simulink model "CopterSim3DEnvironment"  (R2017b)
settings: Solver=ode4  StartTime=0.0  StopTime=2000  FixedStep=0.001  RelTol=1e-3
PreLoadFcn:
  | filepath  = fileparts(get_param(bdroot, 'FileName'));
  | cd(filepath);
InitFcn:
  | if exist('Init_control.m','file')
  |      Init_control;
  | end
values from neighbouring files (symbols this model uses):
  Kd_RP_AgngleRate = 0.005    [Init_control.m]    (also in Init.m = 0.001)
  Kd_YAW_AngleRate = 0.05    [Init_control.m]    (also in Init.m = 0)
  Ki_RP_AgngleRate = 0.01    [Init_control.m]    (also in Init.m = 0.02)
  Ki_YAW_AngleRate = 0.8    [Init_control.m]    (also in Init.m = 0.1)
  KiPitchAttitude = 0.0552303199591522 / kFactor    (= 0.0460252666326)    [Init_control.m]
  KiRollAttitude = 0.0552303199591522 / kFactor    (= 0.0460252666326)    [Init_control.m]
  Kp_RP_AgngleRate = 0.55    [Init_control.m]    (also in Init.m = 0.1)
  Kp_RP_ANGLE = 6.5    [Init_control.m]    (also in Init.m)
  Kp_YAW_AngleRate = 3.2    [Init_control.m]    (also in Init.m = 0.3)
  MAX_CONTROL_ANGLE_RATE_Y = 90    [Init_control.m]    (also in Init.m = 200)
  MAX_CONTROL_ANGLE_RP = 45    [Init_control.m]
  ModelInit_RPM = 0    [Init.m]
  ModelParam_envAltitude = -50    [Init.m]
  ModelParam_GlobalNoiseGainSwitch = 0.4    [Init.m]
  ModelParam_GPSEphFinal = 0.3    [Init.m]
  ModelParam_GPSEpvFinal = 0.4    [Init.m]
  ModelParam_GPSFix3DFix = 3    [Init.m]
  ModelParam_GPSSatsVisible = 10    [Init.m]
  ModelParam_motorCr = 842.1    [Init.m]
  ModelParam_motorJm = 0.0001287    [Init.m]
  ModelParam_motorMinThr = 0.05    [Init.m]
  ModelParam_motorT = 0.0214    [Init.m]
  ModelParam_motorWb = 22.83    [Init.m]
  ModelParam_noiseBaroCoupleWithSpeed = 0    [Init.m]
  ModelParam_noiseGPSSampTime = 0.2    [Init.m]
  ModelParam_noisePowerIMU = 0    [Init.m]
  ModelParam_noisePowerOffGainAccel = 0.04    [Init.m]
  ModelParam_noisePowerOffGainAccelZ = 0.03    [Init.m]
  ModelParam_noisePowerOffGainGyro = 0.02    [Init.m]
  ModelParam_noisePowerOffGainGyroZ = 0.025    [Init.m]
  ModelParam_noisePowerOffGainMag = 0.02    [Init.m]
  ModelParam_noisePowerOffGainMagZ = 0.035    [Init.m]
  ModelParam_noisePowerOnGainAccel = 0.8    [Init.m]
  ModelParam_noisePowerOnGainAccelZ = 4.5    [Init.m]
  ModelParam_noisePowerOnGainGyro = 2    [Init.m]
  ModelParam_noisePowerOnGainGyroZ = 1    [Init.m]
  ModelParam_noisePowerOnGainMag = 0.025    [Init.m]
  ModelParam_noisePowerOnGainMagZ = 0.05    [Init.m]
  ModelParam_noiseSampleTimeAccel = 0.001    [Init.m]
  ModelParam_noiseSampleTimeGyro = 0.001    [Init.m]
  ModelParam_noiseSampleTimeMag = 0.01    [Init.m]
  ModelParam_noiseUpperGPS = 0.5    [Init.m]
  ModelParam_noiseUpperWindBodyRatio = 0    [Init.m]
  ModelParam_noiseWindSampTime = 0.001    [Init.m]
  ModelParam_rotorCm = 2.783e-07    [Init.m]
  ModelParam_rotorCt = 1.681e-05    [Init.m]
  ModelParam_timeSampBaro = 0.01    [Init.m]
  ModelParam_uavCCm = [0.0035 0.0039 0.0034]    [Init.m]
  ModelParam_uavCd = 0.055    [Init.m]
  ModelParam_uavDearo = 0.12    [Init.m]
  ModelParam_uavMass = 1.515    [Init.m]
  ModelParam_uavR = 0.225    [Init.m]
  ModelParam_uavType = int8(3)    [Init.m]
undefined symbols (not defined in the file or in its folder): a029, a452, b2ca, be23, CopterSim3DEnvironment, d291, d_i, da57f061, e227219c210b, Earth, earthRadius, f0d8, f8138af1, ff54be59cd06, h_i, ModelParam_GPSEpvInitial, ModelParam_GPSEpvTimeConstant, ModelParam_noiseLowPassFilterCoeAccel, ModelParam_noiseLowPassFilterCoeGyro, ModelParam_timeSamp, Newton, Raphson, Receive, Send, slider, WGS84
libraries: simulink x17, aerolibfltsims x4, aerolibtransform2 x3, sharedtransform x3, aerolibasang x3, aerolibatmos2 x2, sharedutil x2, aerolibutil x2, etargetslib x2, shared6dof x1, aerolibconvert2 x1, aerolibobsolete x1
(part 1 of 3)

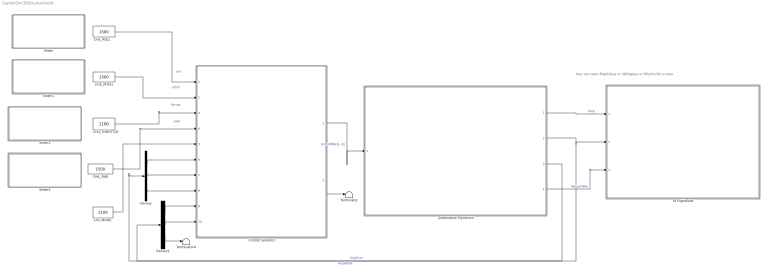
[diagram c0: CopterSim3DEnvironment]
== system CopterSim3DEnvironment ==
  note: Your can open FlightGear or 3DDisplay or RflySim3D to view
  note: roll
  note: pitch
  note: thrust
  note: yaw
  "     CH3_THROTTLR " : Constant  Value=1100  OutDataTypeStr=uint16
  "     CH4_YAW     " : Constant  Value=1500  OutDataTypeStr=uint16
  " CH2_PITCH " : Constant  Value=1500  OutDataTypeStr=uint16
  "CH1_ROLL   " : Constant  Value=1500  OutDataTypeStr=uint16
  "Ch5_MODE " : Constant  Value=1100  OutDataTypeStr=uint16
  Control System1 : Subsystem
  Demux : Demux  Outputs=3
  Demux1 : Demux  Outputs=3
  Quadcopter Dynamics : Subsystem
  Slider : Subsystem  DialogController=hmiCreateDDGDialog  IsWebBlock=on  mask(MWDashboardBlock){webBlockId=da57f061-4e57-426f-be23-e227219c210b, webBlockType=slider, ShowInLibBrowser=on, ShowInitialText=on, HMISrcModelName=CopterSim3DEnvironment}
      mask prompts: webBlockId "WebBlock Id"; webBlockType "WebBlock Type"; HMISrcModelName "Source Model"
      mask help: SimulinkHMI:dialogs:SliderDialogDesc
  Slider1 : Subsystem  DialogController=hmiCreateDDGDialog  IsWebBlock=on  mask(MWDashboardBlock){webBlockId=f8138af1-f0d8-4bb2-b2ca-4a41ecd2e2bf, webBlockType=slider, ShowInLibBrowser=on, ShowInitialText=on, HMISrcModelName=CopterSim3DEnvironment}
      mask prompts: webBlockId "WebBlock Id"; webBlockType "WebBlock Type"; HMISrcModelName "Source Model"
      mask help: SimulinkHMI:dialogs:SliderDialogDesc
  Slider2 : Subsystem  DialogController=hmiCreateDDGDialog  IsWebBlock=on  mask(MWDashboardBlock){webBlockId=6ace0251-812b-4be1-a029-ff54be59cd06, webBlockType=slider, ShowInLibBrowser=on, ShowInitialText=on, HMISrcModelName=CopterSim3DEnvironment}
      mask prompts: webBlockId "WebBlock Id"; webBlockType "WebBlock Type"; HMISrcModelName "Source Model"
      mask help: SimulinkHMI:dialogs:SliderDialogDesc
  Slider3 : Subsystem  DialogController=hmiCreateDDGDialog  IsWebBlock=on  mask(MWDashboardBlock){webBlockId=7791c665-d291-46cf-a452-489177f2fb62, webBlockType=slider, ShowInLibBrowser=on, ShowInitialText=on, HMISrcModelName=CopterSim3DEnvironment}
      mask prompts: webBlockId "WebBlock Id"; webBlockType "WebBlock Type"; HMISrcModelName "Source Model"
      mask help: SimulinkHMI:dialogs:SliderDialogDesc
  Terminator : Terminator
  Terminator4 : Terminator
  To FlightGear : Subsystem
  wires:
  Quadcopter Dynamics/1(PosE) -> To FlightGear/1(PosE)  "PosE"
  Control System1/2(LED) -> Terminator/1
  Quadcopter Dynamics/2(AngEuler) -> To FlightGear/2(AngEular), Demux1/1  "AngEular"
  "CH1_ROLL   "/1 -> Control System1/1(ch1)
  "     CH4_YAW     "/1 -> Control System1/4(ch4)
  "     CH3_THROTTLR "/1 -> Control System1/3(ch3)
  Quadcopter Dynamics/3(AngRateB) -> Demux/1  "AngRateB"
  "Ch5_MODE "/1 -> Control System1/5(ch5)
  Demux/1 -> Control System1/6(p)
  Demux/2 -> Control System1/7(q)
  Demux/3 -> Control System1/8(r)
  Demux1/1 -> Control System1/9(phi)
  Demux1/2 -> Control System1/10(theta)
  Demux1/3 -> Terminator4/1
  " CH2_PITCH "/1 -> Control System1/2(ch2)
  Control System1/1(PWM) -> Quadcopter Dynamics/1(inPWMs)  "8-D PWMs（0~1）"
  Quadcopter Dynamics/4(MotorRPMS) -> To FlightGear/3(MotorPWMs)  "MotorPWMs"

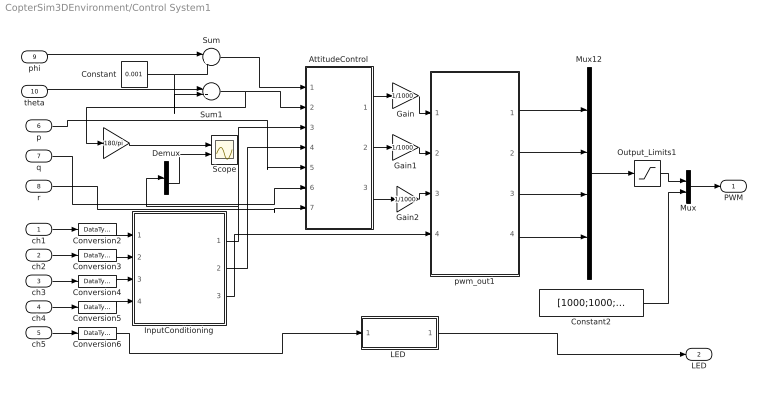
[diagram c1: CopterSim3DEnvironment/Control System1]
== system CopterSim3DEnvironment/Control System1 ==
  ch1 : Inport  OutDataTypeStr=uint16  PortDimensions=1
  ch2 : Inport  Port=2  OutDataTypeStr=uint16  PortDimensions=1
  ch3 : Inport  Port=3  OutDataTypeStr=uint16  PortDimensions=1
  ch4 : Inport  Port=4  OutDataTypeStr=uint16  PortDimensions=1
  ch5 : Inport  Port=5  OutDataTypeStr=uint16  PortDimensions=1  Interpolate=off
  p : Inport  Port=6  PortDimensions=1
  q : Inport  Port=7  PortDimensions=1
  r : Inport  Port=8  PortDimensions=1
  phi : Inport  Port=9  PortDimensions=1
  theta : Inport  Port=10  PortDimensions=1
  " " : Gain  Gain=180/pi
  AttitudeControl : Subsystem
  Constant : Constant  Value=0.001
  Constant2 : Constant  Value=[1000;1000;1000;1000]
  Conversion{2..6} (5 alike) : DataTypeConversion  OutDataTypeStr=double
  Demux : Demux  Outputs=2
  Gain : Gain  Gain=1/1000
  Gain1 : Gain  Gain=1/1000
  Gain2 : Gain  Gain=1/1000
  InputConditioning : Subsystem
  "LED " : Subsystem
  Mux : Mux  Inputs=2
  Mux12 : Mux
  Output_Limits1 : Saturate  UpperLimit=2000  LowerLimit=1000
  Scope : Scope  NumInputPorts=2
  Sum : Sum  Inputs=|++
  Sum1 : Sum  Inputs=|++
  pwm_out1 : MATLAB Function  TreatAsAtomicUnit=on  SystemSampleTime=0.004
  PWM : Outport  PortDimensions=8
  LED : Outport  Port=2  PortDimensions=1
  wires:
  InputConditioning/3(Thrust) -> pwm_out1/4(Thrust)
  Mux12/1 -> Output_Limits1/1
  Gain1/1 -> pwm_out1/2(Pitch)
  Gain/1 -> pwm_out1/1(Roll)
  ch3/1 -> Conversion4/1
  pwm_out1/1(M1) -> Mux12/1
  ch5/1 -> Conversion6/1
  pwm_out1/3(M3) -> Mux12/3
  pwm_out1/2(M2) -> Mux12/2
  r/1 -> AttitudeControl/7(r)
  AttitudeControl/1(Roll) -> Gain/1
  Gain2/1 -> pwm_out1/3(Yaw)
  InputConditioning/1(Roll_Pitch) -> Demux/1, AttitudeControl/3(roll_pitch)
  q/1 -> AttitudeControl/6(q)
  theta/1 -> Sum1/1
  InputConditioning/2(Yaw) -> AttitudeControl/4(yaw)
  p/1 -> AttitudeControl/5(p)
  ch4/1 -> Conversion5/1
  pwm_out1/4(M4) -> Mux12/4
  AttitudeControl/3(Yaw) -> Gain2/1
  AttitudeControl/2(Pitch) -> Gain1/1
  ch1/1 -> Conversion2/1
  "LED "/1(Out1) -> LED/1
  ch2/1 -> Conversion3/1
  Conversion6/1 -> "LED "/1(In1)
  Conversion2/1 -> InputConditioning/1(roll)
  Conversion5/1 -> InputConditioning/4(yaw)
  Conversion4/1 -> InputConditioning/3(thrust)
  Conversion3/1 -> InputConditioning/2(pitch)
  " "/1 -> Scope/1
  Demux/2 -> Scope/2
  phi/1 -> Sum/1
  Sum/1 -> AttitudeControl/1(phi)
  Sum1/1 -> " "/1, AttitudeControl/2(theta)
  Constant/1 -> Sum1/2, Sum/2
  Constant2/1 -> Mux/2
  Output_Limits1/1 -> Mux/1
  Mux/1 -> PWM/1

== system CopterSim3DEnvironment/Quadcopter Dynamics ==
  note: 电机转速
  note: 机体角速度
  note: 欧拉角
  note: 地面坐标系下位置
  note: 地面坐标系下速度
  note: 输入为8路1000~2000范围的信号
  note: Note2: There are three parameters essential for DLL model generation. They are "ModelInit_Inputs" (8D vector for input pwm signal initialization) in the "Motor Model" module, "ModelInit_PosE" (3D vector for position initialization) and "ModelInit_AngEuler" (3D vector for attitude initialization) in the "6DOF" module
  inPWMs : Inport  PortDimensions=8
  6DOF : Subsystem
  Bus Selector : BusSelector  OutputSignals=PosE,AngEuler,MotorRPMS,RateB
  Constant1 : Constant  Value=0
  Constant4 : Constant  Value=[1000;1000;1000;1000;1000;1000;1000;1000]
  Data Type Conversion{,1..3} (4 alike) : DataTypeConversion  OutDataTypeStr=double
  Environment Model : Subsystem
  Force and Moment Model : Subsystem
  Gain1 : Gain  Gain=1/1000
  Motor Model : Subsystem
  OutputSignals : Subsystem
  Rate Transition : RateTransition  OutPortSampleTime=ModelParam_BusSampleRate
  Rate Transition1 : RateTransition  OutPortSampleTime=ModelParam_BusSampleRate
  Selector : Selector  InputPortWidth=8  IndexOptions=Index vector (dialog)  Indices=[1 2 3 4]  OutputSizes=1
  SensorModel : Subsystem
  Sum3 : Sum  Inputs=|+-
  Terminator : Terminator
  Terminator1 : Terminator
  PosE : Outport
  AngEuler : Outport  Port=2
  AngRateB : Outport  Port=3
  MotorRPMS : Outport  Port=4
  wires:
  Selector/1 -> MotorRPMS/1
  Constant4/1 -> Sum3/2
  inPWMs/1 -> Sum3/1
  Constant1/1 -> Rate Transition1/1
  Sum3/1 -> Gain1/1
  Gain1/1 -> Rate Transition/1
  OutputSignals/17(PWMs) -> SensorModel/17(PWM)
  OutputSignals/13(<Rho>) -> SensorModel/13(<Rho>)
  OutputSignals/6(<wb>) -> SensorModel/6(<wb>)
  SensorModel/3(Vehile3DInfo) -> Bus Selector/1
  OutputSignals/12(<AirPressure>) -> SensorModel/12(<AirPressure>)
  OutputSignals/3(<Xe>) -> SensorModel/3(<Xe>)
  OutputSignals/5(<DCM>) -> SensorModel/5(<DCM>)
  OutputSignals/7(<dwb/dt>) -> SensorModel/7(<dwb/dt>)
  OutputSignals/9(<PosGPS>) -> SensorModel/9(<PosGPS>)
  OutputSignals/4(<Eular(rad)>) -> SensorModel/4(<Eular(rad)>)
  OutputSignals/10(<gravity>) -> SensorModel/10(<gravity>)
  OutputSignals/2(<Ve>) -> SensorModel/2(<Ve>)
  OutputSignals/16(<Fb>) -> SensorModel/16(<Fb>)
  OutputSignals/8(<AccB>) -> SensorModel/8(<AccB>)
  OutputSignals/15(<MotorRads>) -> SensorModel/15(MotorRads)
  Force and Moment Model/1(Force and Moment Model Bus) -> OutputSignals/4(Force and Moment Model Bus), 6DOF/1(Force and Moment Model Bus)  "Kinetics Info"
  Rate Transition/1 -> OutputSignals/6(PWM), Motor Model/1(pwm)
  SensorModel/1(MavLinkSensorData) -> Terminator/1
  6DOF/1(6DOF Bus) -> OutputSignals/5(6DOF Bus), Environment Model/1(6DOF Bus), Force and Moment Model/3(6DOF Bus)  "Kinematics Info"
  Rate Transition1/1 -> Force and Moment Model/4("tZ "), OutputSignals/3(zt)
  Motor Model/1(MotorRads) -> OutputSignals/2(MotorRads), Force and Moment Model/1(MotorRads)
  OutputSignals/1(TerrainZ) -> SensorModel/1(TerrainZ)
  OutputSignals/11(<TempC>) -> SensorModel/11(<TempC>)
  Environment Model/1(Environment Model Bus) -> OutputSignals/1(Environment Model Bus), Force and Moment Model/2(Environment Model Bus)  "Environment Info"
  OutputSignals/14(<Windb>) -> SensorModel/14(<Windb>)
  SensorModel/2(MavLinkGPSData) -> Terminator1/1
  Bus Selector/1 -> Data Type Conversion/1  "<PosE>"
  Bus Selector/2 -> Data Type Conversion1/1  "<AngEuler>"
  Bus Selector/4 -> Data Type Conversion3/1  "<RateB>"
  Bus Selector/3 -> Data Type Conversion2/1  "<MotorRPMS>"
  Data Type Conversion/1 -> PosE/1
  Data Type Conversion1/1 -> AngEuler/1
  Data Type Conversion2/1 -> Selector/1
  Data Type Conversion3/1 -> AngRateB/1

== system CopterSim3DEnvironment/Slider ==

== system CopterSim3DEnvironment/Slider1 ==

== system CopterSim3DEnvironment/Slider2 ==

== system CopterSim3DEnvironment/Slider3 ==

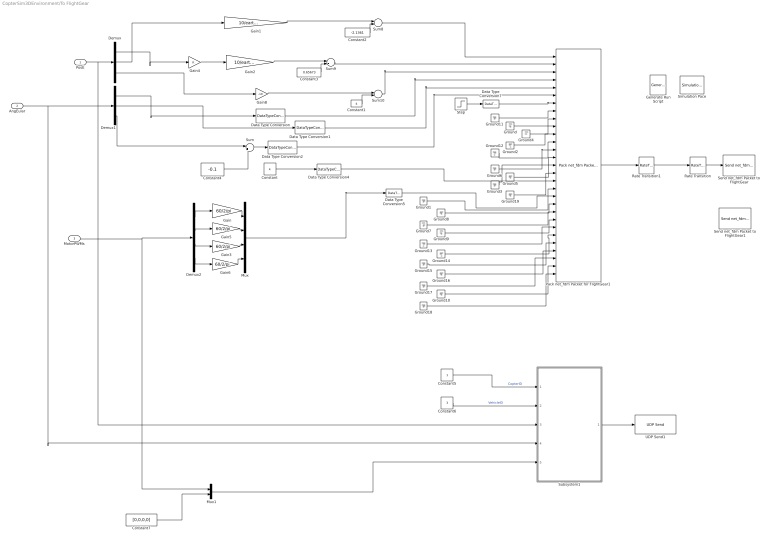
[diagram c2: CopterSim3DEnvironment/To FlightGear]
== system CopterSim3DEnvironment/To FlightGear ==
  PosE : Inport
  AngEular : Inport  Port=2
  MotorPWMs : Inport  Port=3
  Constant : Constant  Value=4
  Constant1 : Constant  Value=5  VectorParams1D=off
  Constant2 : Constant  Value=-2.1361  VectorParams1D=off
  Constant3 : Constant  Value=0.65673  VectorParams1D=off
  Constant4 : Constant  Value=-0.1  VectorParams1D=off
  Constant5 : Constant
  Constant6 : Constant  Value=3
  Constant7 : Constant  Value=[0,0,0,0]
  Data Type Conversion{,1..2,5,7} (5 alike) : DataTypeConversion  OutDataTypeStr=single
  Data Type Conversion4 : DataTypeConversion  OutDataTypeStr=uint32
  Demux : Demux  Outputs=3
  Demux1 : Demux  Outputs=3
  Demux2 : Demux
  Gain{,3,5..6} (4 alike) : Gain  Gain=60/2/pi
  Gain1 : Gain  Gain=10/earthRadius
  Gain2 : Gain  Gain=10/earthRadius
  Gain4 : Gain
  Gain8 : Gain  Gain=-10
  Generate Run Script : aerolibfltsims/Generate Run Script  OutputFileName=runfg.bat  FlightGearBaseDirectory=C:\Program Files\FlightGear 2016.1.2  GeometryModelName=Rotor4  DestinationPort=5502  OriginAddress=127.0.0.1  OriginPort=5505  LocalAddress=127.0.0.1  AirportId=KSF0  RunwayId=10L  InitialAltitude=0  InitialHeading=0  OffsetDistance=0  OffsetAzimuth=0  GenerateFile=off  Architecture=Default  dataFlow=Send-Receive
  Ground{,1..19} (20 alike) : Ground
  Mux : Mux
  Mux1 : Mux  Inputs=2
  Pack net_fdm Packet for FlightGear1 : aerolibfltsims/Pack net_fdm Packet for FlightGear  FlightGearVersion=v2016.1  ShowPositionAttitudeInputs=on  ShowVelocityAccelerationInputs=off  ShowControlSurfacePositionInputs=on  ShowEngineFuelInputs=on  ShowLandingGearInputs=off  ShowEnvironmentInputs=off  SampleTime=0.01
  Rate Transition : RateTransition
  Rate Transition1 : RateTransition
  Send net_fdm Packet to FlightGear : aerolibfltsims/Send net_fdm Packet to FlightGear  DestinationIpAddress=127.0.0.1  DestinationPort=5502  LocalIpPort=-1  varLen=off  SampleTime=0.005
  Send net_fdm Packet to FlightGear1 : aerolibfltsims/Send net_fdm Packet to FlightGear  Commented=on  DestinationIpAddress=192.168.199.46  DestinationPort=5502  LocalIpPort=-1  varLen=off  SampleTime=0.01
  Simulation Pace : aerolibanimutils/Simulation Pace  SimulationPace=1  SleepMode=MATLAB Thread  OutputPaceError=off  SampleTime=-1
  Step : Step  Time=5  SampleTime=0
  Subsystem1 : Subsystem
  Sum{,8..10} (4 alike) : Sum  Inputs=|++
  UDP Send1 : dspnetwork/UDP Send  remoteURL='127.0.0.1'  remotePort=20010  localURL='0.0.0.0'  localPortSource=Automatically determine  localPort=-1  sampletime=-1  blockPlatform=[]  separateLengthPort=0
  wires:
  Rate Transition/1 -> Send net_fdm Packet to FlightGear/1
  Demux/1 -> Gain4/1
  Demux/2 -> Gain1/1
  Demux/3 -> Gain8/1
  Constant4/1 -> Sum/2
  Sum/1 -> Data Type Conversion2/1
  Gain1/1 -> Sum8/1
  Constant2/1 -> Sum8/2
  Gain2/1 -> Sum9/1
  Constant3/1 -> Sum9/2
  Constant1/1 -> Sum10/2
  Gain8/1 -> Sum10/1
  Pack net_fdm Packet for FlightGear1/1 -> Rate Transition1/1
  Demux1/2 -> Data Type Conversion1/1
  Demux1/3 -> Sum/1
  Data Type Conversion7/1 -> Pack net_fdm Packet for FlightGear1/7
  Ground8/1 -> Pack net_fdm Packet for FlightGear1/20
  Ground/1 -> Pack net_fdm Packet for FlightGear1/9
  Ground7/1 -> Pack net_fdm Packet for FlightGear1/21
  Ground9/1 -> Pack net_fdm Packet for FlightGear1/22
  Ground13/1 -> Pack net_fdm Packet for FlightGear1/23
  Ground14/1 -> Pack net_fdm Packet for FlightGear1/24
  Ground15/1 -> Pack net_fdm Packet for FlightGear1/25
  Ground16/1 -> Pack net_fdm Packet for FlightGear1/26
  Ground17/1 -> Pack net_fdm Packet for FlightGear1/27
  Ground10/1 -> Pack net_fdm Packet for FlightGear1/28
  Ground18/1 -> Pack net_fdm Packet for FlightGear1/29
  Step/1 -> Data Type Conversion7/1
  Data Type Conversion4/1 -> Pack net_fdm Packet for FlightGear1/17
  Ground1/1 -> Pack net_fdm Packet for FlightGear1/18
  Ground3/1 -> Pack net_fdm Packet for FlightGear1/15
  Ground5/1 -> Pack net_fdm Packet for FlightGear1/14
  Ground6/1 -> Pack net_fdm Packet for FlightGear1/13
  Ground4/1 -> Pack net_fdm Packet for FlightGear1/10
  Ground11/1 -> Pack net_fdm Packet for FlightGear1/8
  Data Type Conversion2/1 -> Pack net_fdm Packet for FlightGear1/6
  Data Type Conversion1/1 -> Pack net_fdm Packet for FlightGear1/5
  Data Type Conversion/1 -> Pack net_fdm Packet for FlightGear1/4
  Sum8/1 -> Pack net_fdm Packet for FlightGear1/1
  Sum9/1 -> Pack net_fdm Packet for FlightGear1/2
  Sum10/1 -> Pack net_fdm Packet for FlightGear1/3
  Constant/1 -> Data Type Conversion4/1
  Data Type Conversion5/1 -> Pack net_fdm Packet for FlightGear1/19
  Ground2/1 -> Pack net_fdm Packet for FlightGear1/11
  Ground12/1 -> Pack net_fdm Packet for FlightGear1/12
  Ground19/1 -> Pack net_fdm Packet for FlightGear1/16
  Gain4/1 -> Gain2/1
  MotorPWMs/1 -> Mux1/1, Demux2/1
  Mux/1 -> Data Type Conversion5/1
  Demux2/1 -> Gain/1
  Demux2/3 -> Gain3/1
  Gain/1 -> Mux/1
  Gain3/1 -> Mux/3
  Demux2/2 -> Gain5/1
  Gain5/1 -> Mux/2
  Demux2/4 -> Gain6/1
  Gain6/1 -> Mux/4
  Demux1/1 -> Data Type Conversion/1
  Rate Transition1/1 -> Rate Transition/1
  Constant6/1 -> Subsystem1/2(vehicleType)  "VehicleID"
  PosE/1 -> Subsystem1/3(PosE), Demux/1
  Constant5/1 -> Subsystem1/1(copterID)  "CopterID"
  Subsystem1/1(toUnReal) -> UDP Send1/1
  AngEular/1 -> Demux1/1, Subsystem1/4(AngEuler)
  Constant7/1 -> Mux1/2
  Mux1/1 -> Subsystem1/5(pwms)

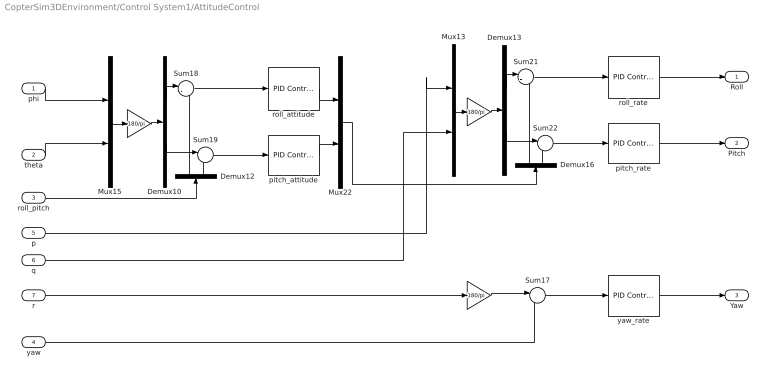
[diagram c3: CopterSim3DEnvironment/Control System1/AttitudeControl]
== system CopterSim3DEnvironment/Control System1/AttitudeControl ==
  phi : Inport
  theta : Inport  Port=2
  roll_pitch : Inport  Port=3
  yaw : Inport  Port=4
  p : Inport  Port=5
  q : Inport  Port=6
  r : Inport  Port=7
  " " : Gain  Gain=180/pi
  "  " : Gain  Gain=180/pi
  "          " : Gain  Gain=180/pi
  Demux{10,12..13,16} (4 alike) : Demux  Outputs=2
  Mux13 : Mux  Inputs=2
  Mux15 : Mux  Inputs=2
  Mux22 : Mux  Inputs=2
  Sum{17..19,21..22} (5 alike) : Sum  Inputs=|-+
  pitch_attitude : simulink/Continuous/PID Controller  Controller=P  TimeDomain=Discrete-time  SampleTime=-1  IntegratorMethod=Forward Euler  FilterMethod=Forward Euler  Form=Parallel  UseFilter=on  ControllerParametersSource=internal  P=Kp_RP_ANGLE  I=KiPitchAttitude  D=0.01  N=100  InitialConditionSource=internal  InitialConditionForIntegrator=0  InitialConditionForFilter=0  ExternalReset=none  LimitOutput=on  UpperSaturationLimit=180  LowerSaturationLimit=-180  LinearizeAsGain=on  AntiWindupMode=back-calculation  Kb=1  TrackingMode=off  Kt=1  PParamMin=[]  PParamMax=[]  IParamMin=[]  IParamMax=[]  DParamMin=[]  DParamMax=[]  NParamMin=[]  NParamMax=[]  KbParamMin=[]  KbParamMax=[]  KtParamMin=[]  KtParamMax=[]  POutMin=[]  POutMax=[]  IOutMin=[]  IOutMax=[]  DOutMin=[]  DOutMax=[]  NOutMin=[]  NOutMax=[]  KbOutMin=[]  KbOutMax=[]  KtOutMin=[]  KtOutMax=[]  IntegratorOutMin=[]  IntegratorOutMax=[]  FilterOutMin=[]  FilterOutMax=[]  SumOutMin=[]  SumOutMax=[]  SumI1OutMin=[]  SumI1OutMax=[]  SumI2OutMin=[]  SumI2OutMax=[]  SumI3OutMin=[]  SumI3OutMax=[]  SumDOutMin=[]  SumDOutMax=[]  SaturationOutMin=[]  SaturationOutMax=[]  IntegratorContinuousStateAttributes=''  IntegratorStateMustResolveToSignalObject=off  IntegratorRTWStateStorageClass=Auto  FilterContinuousStateAttributes=''  FilterStateMustResolveToSignalObject=off  FilterRTWStateStorageClass=Auto  DifferentiatorICPrevScaledInput=0  DifferentiatorOutMin=[]  DifferentiatorOutMax=[]  InitialConditionSetting=State (most efficient)  FilterDiffOutCoefMin=[]  FilterDiffOutCoefMax=[]  SumDenOutMin=[]  SumDenOutMax=[]  SumNumOutMin=[]  SumNumOutMax=[]  ReciprocalOutMin=[]  ReciprocalOutMax=[]  DivideOutMin=[]  DivideOutMax=[]  TunerSelectOption=Transfer Function Based (PID Tuner App)
  pitch_rate : simulink/Continuous/PID Controller  Controller=PID  TimeDomain=Discrete-time  SampleTime=-1  IntegratorMethod=Forward Euler  FilterMethod=Forward Euler  Form=Parallel  UseFilter=off  ControllerParametersSource=internal  P=Kp_RP_AgngleRate  I=Ki_RP_AgngleRate  D=Kd_RP_AgngleRate  N=100  InitialConditionSource=internal  InitialConditionForIntegrator=0  InitialConditionForFilter=0  ExternalReset=none  LimitOutput=on  UpperSaturationLimit=500  LowerSaturationLimit=-500  LinearizeAsGain=on  AntiWindupMode=back-calculation  Kb=1  TrackingMode=off  Kt=1  PParamMin=[]  PParamMax=[]  IParamMin=[]  IParamMax=[]  DParamMin=[]  DParamMax=[]  NParamMin=[]  NParamMax=[]  KbParamMin=[]  KbParamMax=[]  KtParamMin=[]  KtParamMax=[]  POutMin=[]  POutMax=[]  IOutMin=[]  IOutMax=[]  DOutMin=[]  DOutMax=[]  NOutMin=[]  NOutMax=[]  KbOutMin=[]  KbOutMax=[]  KtOutMin=[]  KtOutMax=[]  IntegratorOutMin=[]  IntegratorOutMax=[]  FilterOutMin=[]  FilterOutMax=[]  SumOutMin=[]  SumOutMax=[]  SumI1OutMin=[]  SumI1OutMax=[]  SumI2OutMin=[]  SumI2OutMax=[]  SumI3OutMin=[]  SumI3OutMax=[]  SumDOutMin=[]  SumDOutMax=[]  SaturationOutMin=[]  SaturationOutMax=[]  IntegratorContinuousStateAttributes=''  IntegratorStateMustResolveToSignalObject=off  IntegratorRTWStateStorageClass=Auto  FilterContinuousStateAttributes=''  FilterStateMustResolveToSignalObject=off  FilterRTWStateStorageClass=Auto  DifferentiatorICPrevScaledInput=0  DifferentiatorOutMin=[]  DifferentiatorOutMax=[]  InitialConditionSetting=State (most efficient)  FilterDiffOutCoefMin=[]  FilterDiffOutCoefMax=[]  SumDenOutMin=[]  SumDenOutMax=[]  SumNumOutMin=[]  SumNumOutMax=[]  ReciprocalOutMin=[]  ReciprocalOutMax=[]  DivideOutMin=[]  DivideOutMax=[]  TunerSelectOption=Transfer Function Based (PID Tuner App)
  roll_attitude : simulink/Continuous/PID Controller  Controller=P  TimeDomain=Discrete-time  SampleTime=-1  IntegratorMethod=Forward Euler  FilterMethod=Forward Euler  Form=Parallel  UseFilter=on  ControllerParametersSource=internal  P=Kp_RP_ANGLE  I=KiRollAttitude  D=0.01  N=100  InitialConditionSource=internal  InitialConditionForIntegrator=0  InitialConditionForFilter=0  ExternalReset=none  LimitOutput=on  UpperSaturationLimit=180  LowerSaturationLimit=-180  LinearizeAsGain=on  AntiWindupMode=back-calculation  Kb=1  TrackingMode=off  Kt=1  PParamMin=[]  PParamMax=[]  IParamMin=[]  IParamMax=[]  DParamMin=[]  DParamMax=[]  NParamMin=[]  NParamMax=[]  KbParamMin=[]  KbParamMax=[]  KtParamMin=[]  KtParamMax=[]  POutMin=[]  POutMax=[]  IOutMin=[]  IOutMax=[]  DOutMin=[]  DOutMax=[]  NOutMin=[]  NOutMax=[]  KbOutMin=[]  KbOutMax=[]  KtOutMin=[]  KtOutMax=[]  IntegratorOutMin=[]  IntegratorOutMax=[]  FilterOutMin=[]  FilterOutMax=[]  SumOutMin=[]  SumOutMax=[]  SumI1OutMin=[]  SumI1OutMax=[]  SumI2OutMin=[]  SumI2OutMax=[]  SumI3OutMin=[]  SumI3OutMax=[]  SumDOutMin=[]  SumDOutMax=[]  SaturationOutMin=[]  SaturationOutMax=[]  IntegratorContinuousStateAttributes=''  IntegratorStateMustResolveToSignalObject=off  IntegratorRTWStateStorageClass=Auto  FilterContinuousStateAttributes=''  FilterStateMustResolveToSignalObject=off  FilterRTWStateStorageClass=Auto  DifferentiatorICPrevScaledInput=0  DifferentiatorOutMin=[]  DifferentiatorOutMax=[]  InitialConditionSetting=State (most efficient)  FilterDiffOutCoefMin=[]  FilterDiffOutCoefMax=[]  SumDenOutMin=[]  SumDenOutMax=[]  SumNumOutMin=[]  SumNumOutMax=[]  ReciprocalOutMin=[]  ReciprocalOutMax=[]  DivideOutMin=[]  DivideOutMax=[]  TunerSelectOption=Transfer Function Based (PID Tuner App)
  roll_rate : simulink/Continuous/PID Controller  Controller=PID  TimeDomain=Discrete-time  SampleTime=-1  IntegratorMethod=Forward Euler  FilterMethod=Forward Euler  Form=Parallel  UseFilter=off  ControllerParametersSource=internal  P=Kp_RP_AgngleRate  I=Ki_RP_AgngleRate  D=Kd_RP_AgngleRate  N=100  InitialConditionSource=internal  InitialConditionForIntegrator=0  InitialConditionForFilter=0  ExternalReset=none  LimitOutput=on  UpperSaturationLimit=500  LowerSaturationLimit=-500  LinearizeAsGain=on  AntiWindupMode=back-calculation  Kb=1  TrackingMode=off  Kt=1  PParamMin=[]  PParamMax=[]  IParamMin=[]  IParamMax=[]  DParamMin=[]  DParamMax=[]  NParamMin=[]  NParamMax=[]  KbParamMin=[]  KbParamMax=[]  KtParamMin=[]  KtParamMax=[]  POutMin=[]  POutMax=[]  IOutMin=[]  IOutMax=[]  DOutMin=[]  DOutMax=[]  NOutMin=[]  NOutMax=[]  KbOutMin=[]  KbOutMax=[]  KtOutMin=[]  KtOutMax=[]  IntegratorOutMin=[]  IntegratorOutMax=[]  FilterOutMin=[]  FilterOutMax=[]  SumOutMin=[]  SumOutMax=[]  SumI1OutMin=[]  SumI1OutMax=[]  SumI2OutMin=[]  SumI2OutMax=[]  SumI3OutMin=[]  SumI3OutMax=[]  SumDOutMin=[]  SumDOutMax=[]  SaturationOutMin=[]  SaturationOutMax=[]  IntegratorContinuousStateAttributes=''  IntegratorStateMustResolveToSignalObject=off  IntegratorRTWStateStorageClass=Auto  FilterContinuousStateAttributes=''  FilterStateMustResolveToSignalObject=off  FilterRTWStateStorageClass=Auto  DifferentiatorICPrevScaledInput=0  DifferentiatorOutMin=[]  DifferentiatorOutMax=[]  InitialConditionSetting=State (most efficient)  FilterDiffOutCoefMin=[]  FilterDiffOutCoefMax=[]  SumDenOutMin=[]  SumDenOutMax=[]  SumNumOutMin=[]  SumNumOutMax=[]  ReciprocalOutMin=[]  ReciprocalOutMax=[]  DivideOutMin=[]  DivideOutMax=[]  TunerSelectOption=Transfer Function Based (PID Tuner App)
  yaw_rate : simulink/Continuous/PID Controller  Controller=PID  TimeDomain=Discrete-time  SampleTime=-1  IntegratorMethod=Forward Euler  FilterMethod=Forward Euler  Form=Parallel  UseFilter=off  ControllerParametersSource=internal  P=Kp_YAW_AngleRate  I=Ki_YAW_AngleRate  D=Kd_YAW_AngleRate  N=100  InitialConditionSource=internal  InitialConditionForIntegrator=0  InitialConditionForFilter=0  ExternalReset=none  LimitOutput=on  UpperSaturationLimit=500  LowerSaturationLimit=-500  LinearizeAsGain=on  AntiWindupMode=back-calculation  Kb=1  TrackingMode=off  Kt=1  PParamMin=[]  PParamMax=[]  IParamMin=[]  IParamMax=[]  DParamMin=[]  DParamMax=[]  NParamMin=[]  NParamMax=[]  KbParamMin=[]  KbParamMax=[]  KtParamMin=[]  KtParamMax=[]  POutMin=[]  POutMax=[]  IOutMin=[]  IOutMax=[]  DOutMin=[]  DOutMax=[]  NOutMin=[]  NOutMax=[]  KbOutMin=[]  KbOutMax=[]  KtOutMin=[]  KtOutMax=[]  IntegratorOutMin=[]  IntegratorOutMax=[]  FilterOutMin=[]  FilterOutMax=[]  SumOutMin=[]  SumOutMax=[]  SumI1OutMin=[]  SumI1OutMax=[]  SumI2OutMin=[]  SumI2OutMax=[]  SumI3OutMin=[]  SumI3OutMax=[]  SumDOutMin=[]  SumDOutMax=[]  SaturationOutMin=[]  SaturationOutMax=[]  IntegratorContinuousStateAttributes=''  IntegratorStateMustResolveToSignalObject=off  IntegratorRTWStateStorageClass=Auto  FilterContinuousStateAttributes=''  FilterStateMustResolveToSignalObject=off  FilterRTWStateStorageClass=Auto  DifferentiatorICPrevScaledInput=0  DifferentiatorOutMin=[]  DifferentiatorOutMax=[]  InitialConditionSetting=State (most efficient)  FilterDiffOutCoefMin=[]  FilterDiffOutCoefMax=[]  SumDenOutMin=[]  SumDenOutMax=[]  SumNumOutMin=[]  SumNumOutMax=[]  ReciprocalOutMin=[]  ReciprocalOutMax=[]  DivideOutMin=[]  DivideOutMax=[]  TunerSelectOption=Transfer Function Based (PID Tuner App)
  Roll : Outport
  Pitch : Outport  Port=2
  Yaw : Outport  Port=3
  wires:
  r/1 -> "          "/1
  q/1 -> Mux13/2
  Mux22/1 -> Demux16/1
  yaw_rate/1 -> Yaw/1
  phi/1 -> Mux15/1
  Mux15/1 -> " "/1
  theta/1 -> Mux15/2
  "          "/1 -> Sum17/1
  roll_rate/1 -> Roll/1
  Sum19/1 -> pitch_attitude/1
  pitch_attitude/1 -> Mux22/2
  roll_attitude/1 -> Mux22/1
  Demux16/1 -> Sum21/2
  yaw/1 -> Sum17/2
  roll_pitch/1 -> Demux12/1
  Demux16/2 -> Sum22/2
  Demux12/1 -> Sum18/2
  Demux12/2 -> Sum19/2
  p/1 -> Mux13/1
  Demux10/1 -> Sum18/1
  Demux10/2 -> Sum19/1
  " "/1 -> Demux10/1
  Sum18/1 -> roll_attitude/1
  pitch_rate/1 -> Pitch/1
  Mux13/1 -> "  "/1
  Sum22/1 -> pitch_rate/1
  Sum17/1 -> yaw_rate/1
  Demux13/1 -> Sum21/1
  Demux13/2 -> Sum22/1
  "  "/1 -> Demux13/1
  Sum21/1 -> roll_rate/1

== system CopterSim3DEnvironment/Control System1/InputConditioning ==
  note: Roll Angle limit: 0.5 rad
  note: Normalization
  roll : Inport
  pitch : Inport  Port=2
  thrust : Inport  Port=3
  yaw : Inport  Port=4
  Fcn2 : Fcn  Expr=(u - 1500)/400
  Fcn5 : Fcn  Expr=(u - 1500)/400
  Fcn6 : Fcn  Expr=(u - 1100) / 800
  Fcn7 : Fcn  Expr=(u - 1500)/400
  Gain : Gain  Gain=MAX_CONTROL_ANGLE_RATE_Y
  Gain1 : Gain  Gain=0.5
  Gain2 : Gain  Gain=[MAX_CONTROL_ANGLE_RP MAX_CONTROL_ANGLE_RP]  OutDataTypeStr=Inherit: Inherit via back propagation
  Gain3 : Gain  Gain=0.5
  Gain4 : Gain  Gain=0.5
  MATLAB Function : MATLAB Function  TreatAsAtomicUnit=on
  MATLAB Function1 : MATLAB Function  TreatAsAtomicUnit=on
  MATLAB Function2 : MATLAB Function  TreatAsAtomicUnit=on
  MATLAB Function3 : MATLAB Function  TreatAsAtomicUnit=on
  Mux21 : Mux  Inputs=2
  Saturation10 : Saturate  UpperLimit=1  LowerLimit=0
  Saturation7 : Saturate  UpperLimit=1  LowerLimit=-1
  Saturation8 : Saturate  UpperLimit=1  LowerLimit=-1
  Saturation9 : Saturate  UpperLimit=1  LowerLimit=-1
  Roll_Pitch : Outport
  Yaw : Outport  Port=2
  Thrust : Outport  Port=3
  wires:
  Saturation10/1 -> Thrust/1
  Saturation7/1 -> Gain/1
  Gain2/1 -> Roll_Pitch/1
  Mux21/1 -> Gain2/1
  Saturation8/1 -> Mux21/2
  Fcn6/1 -> Saturation10/1
  Fcn2/1 -> Gain1/1
  Fcn5/1 -> Gain3/1
  Saturation9/1 -> Mux21/1
  Fcn7/1 -> Gain4/1
  pitch/1 -> MATLAB Function2/1(u)
  MATLAB Function1/1(y) -> Fcn7/1
  thrust/1 -> MATLAB Function3/1(u)
  roll/1 -> MATLAB Function/1(u)
  MATLAB Function2/1(y) -> Fcn5/1
  MATLAB Function/1(y) -> Fcn2/1
  yaw/1 -> MATLAB Function1/1(u)
  MATLAB Function3/1(y) -> Fcn6/1
  Gain/1 -> Yaw/1
  Gain1/1 -> Saturation9/1
  Gain3/1 -> Saturation8/1
  Gain4/1 -> Saturation7/1

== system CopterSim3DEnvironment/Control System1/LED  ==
  In1 : Inport
  Compare To Constant3 : simulink/Logic and Bit Operations/Compare To Constant  relop=>=  const=uint16(1500)  OutDataTypeStr=boolean
  Out1 : Outport
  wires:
  Compare To Constant3/1 -> Out1/1
  In1/1 -> Compare To Constant3/1

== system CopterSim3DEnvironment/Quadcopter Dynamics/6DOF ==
  Force and Moment Model Bus : Inport
  Bus Creator : BusCreator  Inputs=8
  Bus Selector1 : BusSelector  OutputSignals=Fb,Mb
  Custom Variable Mass 6DOF (Quaternion) : shared6dof/6DOF (Euler Angles)  units=Metric (MKS)  mtype=Fixed  rep=Quaternion  xme_0=ModelInit_PosE  Vm_0=ModelInit_VelB  eul_0=ModelInit_AngEuler  pm_0=ModelInit_RateB  mass_0=ModelParam_uavMass  mass_e=0.5  mass_f=2.0  inertia=ModelParam_uavJ  inertia_e=eye(3)  inertia_f=2*eye(3)  k_quat=1.0  vre_flag=off  abi_flag=off
  6DOF Bus : Outport
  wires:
  Bus Selector1/1 -> Custom Variable Mass 6DOF (Quaternion)/1  "<Fb>"
  Custom Variable Mass 6DOF (Quaternion)/8 -> Bus Creator/8  "AccB"
  Custom Variable Mass 6DOF (Quaternion)/5 -> Bus Creator/5  "Vb"
  Custom Variable Mass 6DOF (Quaternion)/6 -> Bus Creator/6  "wb"
  Custom Variable Mass 6DOF (Quaternion)/1 -> Bus Creator/1  "Ve"
  Custom Variable Mass 6DOF (Quaternion)/4 -> Bus Creator/4  "DCM"
  Custom Variable Mass 6DOF (Quaternion)/2 -> Bus Creator/2  "Xe"
  Custom Variable Mass 6DOF (Quaternion)/3 -> Bus Creator/3  "Eular(rad)"
  Custom Variable Mass 6DOF (Quaternion)/7 -> Bus Creator/7  "dwb/dt"
  Bus Selector1/2 -> Custom Variable Mass 6DOF (Quaternion)/2  "<Mb>"
  Force and Moment Model Bus/1 -> Bus Selector1/1
  Bus Creator/1 -> 6DOF Bus/1

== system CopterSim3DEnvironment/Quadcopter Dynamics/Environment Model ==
  6DOF Bus : Inport
  Bus Creator : BusCreator  Inputs=6
  Bus Selector : BusSelector  OutputSignals=Xe,Vb
  Constant_[1 1 1] : Constant  Value=[1,1,1]  VectorParams1D=off
  Flat Earth to LLA : aerolibtransform2/Flat Earth to LLA  units=Metric (MKS)  ptype=Earth (WGS84)  F=1/298.257223563  R=6378137  LL0=ModelParam_GPSLatLong  psi=0
  ISA Atmosphere Model : aerolibatmos2/ISA Atmosphere Model  custom=off  g=9.80665  gamma=1.4  R=287.0531  L=0.0065  h_trop=11000  h_strat=20000  rho0=1.225  P0=101325  T0=288.15  h0=0
  ModelParam.envAltitude : Constant  Value=ModelParam_envAltitude
  ModelParam.noiseUpperWindBodyRatio : Gain  Gain=ModelParam_noiseUpperWindBodyRatio
  ModelParam.noiseUpperWindBodyRatioSwitch : Gain  Gain=ModelParam_GlobalNoiseGainSwitch
  Mux : Mux  Inputs=2
  Product1 : Product
  Reshape : Reshape
  Saturation : Saturate  UpperLimit=100000  LowerLimit=0
  Sum1 : Sum  Inputs=|++
  Temperature Conversion : aerolibconvert2/Temperature Conversion  IU=K  OU=C
  TemperatureConstant : Constant  Value=25
  Terminator2 : Terminator
  Terminator3 : Terminator
  Uniform Random Number : UniformRandomNumber  Minimum=[-1,-1,-0.5]  Maximum=[1,1,0.5]  Seed=[564565,6846798,46545]  SampleTime=ModelParam_noiseWindSampTime
  "WGS84 Gravity Model " : aerolibobsolete/WGS84 Gravity Model   model=WGS84 Taylor Series  units=Metric (MKS)  no_atmos=on  precessing=on  jd_loc=off  month=October  day=10  year=2004  no_centrifugal=on  action=Warning
  Environment Model Bus : Outport
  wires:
  "WGS84 Gravity Model "/1 -> Reshape/1
  Reshape/1 -> Bus Creator/2  "gravity"
  ISA Atmosphere Model/1 -> Temperature Conversion/1
  ISA Atmosphere Model/2 -> Terminator3/1
  ISA Atmosphere Model/3 -> Bus Creator/4  "AirPressure"
  ISA Atmosphere Model/4 -> Bus Creator/5  "Rho"
  ModelParam.envAltitude/1 -> Flat Earth to LLA/2
  Mux/1 -> Bus Creator/1, "WGS84 Gravity Model "/1  "PosGPS"
  Flat Earth to LLA/1 -> Mux/1
  Bus Selector/2 -> Product1/2  "<Vb>"
  Uniform Random Number/1 -> ModelParam.noiseUpperWindBodyRatio/1
  Product1/1 -> Bus Creator/6  "Windb"
  Constant_[1 1 1]/1 -> Sum1/1
  ModelParam.noiseUpperWindBodyRatio/1 -> ModelParam.noiseUpperWindBodyRatioSwitch/1
  Sum1/1 -> Product1/1
  Temperature Conversion/1 -> Terminator2/1
  TemperatureConstant/1 -> Bus Creator/3  "TempC"
  ModelParam.noiseUpperWindBodyRatioSwitch/1 -> Sum1/2
  6DOF Bus/1 -> Bus Selector/1
  Bus Selector/1 -> Flat Earth to LLA/1  "<Xe>"
  Bus Creator/1 -> Environment Model Bus/1
  Flat Earth to LLA/2 -> Mux/2, Saturation/1
  Saturation/1 -> ISA Atmosphere Model/1

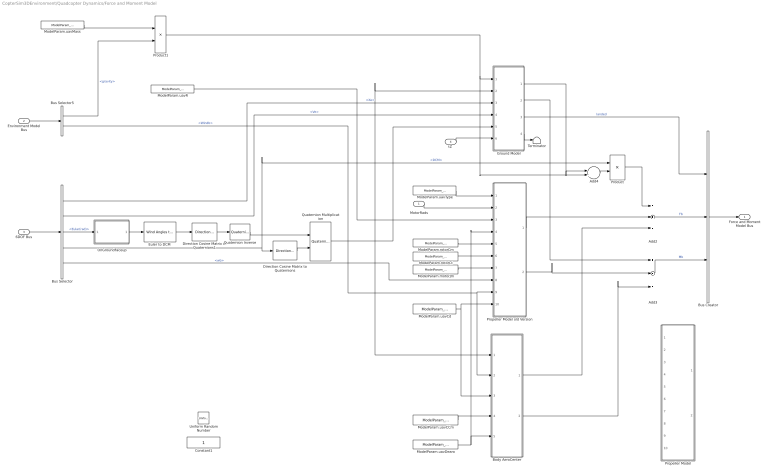
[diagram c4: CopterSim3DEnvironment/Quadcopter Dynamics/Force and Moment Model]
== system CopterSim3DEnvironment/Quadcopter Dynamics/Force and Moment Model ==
  MotorRads : Inport
  Environment Model Bus : Inport  Port=2
  6DOF Bus : Inport  Port=3
  "tZ " : Inport  Port=4
  Add2 : Sum  Inputs=+++
  Add3 : Sum  Inputs=+++
  Add4 : Sum
  Body AeroCenter : MATLAB Function  TreatAsAtomicUnit=on
  Bus Creator : BusCreator  Inputs=3
  Bus Selector : BusSelector  OutputSignals=Xe,Ve,Eular(rad),DCM,wb
  Bus Selector5 : BusSelector  OutputSignals=gravity,Windb
  Constant1 : Constant  Commented=on
  Direction Cosine Matrix to Quaternions : sharedtransform/Direction Cosine Matrix  to Quaternions
  Direction Cosine Matrix to Quaternions1 : sharedtransform/Direction Cosine Matrix  to Quaternions
  Euler to DCM : aerolibtransform2/Wind Angles to  Direction Cosine Matrix
  Ground Model : MATLAB Function  TreatAsAtomicUnit=on
  ModelParam.motorJm : Constant  Value=ModelParam_motorJm
  ModelParam.rotorCm : Constant  Value=ModelParam_rotorCm
  ModelParam.rotorCt : Constant  Value=ModelParam_rotorCt
  ModelParam.uavCCm : Constant  Value=ModelParam_uavCCm
  ModelParam.uavCd : Constant  Value=ModelParam_uavCd
  ModelParam.uavDearo : Constant  Value=ModelParam_uavDearo
  ModelParam.uavMass : Constant  Value=ModelParam_uavMass
  ModelParam.uavR : Constant  Value=ModelParam_uavR
  ModelParam.uavType : Constant  Value=ModelParam_uavType
  OnGroundFaceup : MATLAB Function  TreatAsAtomicUnit=on
  Product : Product  Multiplication=Matrix(*)
  Product1 : Product
  Propeller Model : Subsystem  Commented=on  TreatAsAtomicUnit=on
  Propeller Model old Version : MATLAB Function  TreatAsAtomicUnit=on
  Quaternion Inverse : aerolibutil/Quaternion Inverse
  Quaternion Multiplication : aerolibutil/Quaternion Multiplication
  Terminator : Terminator
  Uniform Random Number : UniformRandomNumber  Commented=on  Minimum=[-1,-1,-1]  Maximum=[1,1,1]  Seed=[145787,351545,2864]  SampleTime=0.05
  Force and Moment Model Bus : Outport
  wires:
  Body AeroCenter/2(Md) -> Add3/3
  Body AeroCenter/1(Fd) -> Add2/3
  Propeller Model old Version/2(Mb) -> Add3/2
  Propeller Model old Version/1(Fb) -> Add2/2
  Ground Model/4(takeoff) -> Terminator/1
  Ground Model/3(landed) -> Bus Creator/1  "landed"
  "tZ "/1 -> Ground Model/6(terrainZ)
  Add3/1 -> Bus Creator/3  "Mb"
  Add2/1 -> Bus Creator/2  "Fb"
  ModelParam.uavType/1 -> Propeller Model old Version/1(uavType)
  Quaternion Multiplication/1 -> Ground Model/5(Quet)
  Quaternion Inverse/1 -> Quaternion Multiplication/1
  Direction Cosine Matrix to Quaternions1/1 -> Quaternion Inverse/1
  Euler to DCM/1 -> Direction Cosine Matrix to Quaternions1/1
  OnGroundFaceup/1(y) -> Euler to DCM/1
  Direction Cosine Matrix to Quaternions/1 -> Quaternion Multiplication/2
  ModelParam.rotorCt/1 -> Propeller Model old Version/6(Ct)
  Product/1 -> Add2/1
  Ground Model/1(F1) -> Add4/1
  Add4/1 -> Product/2
  Product1/1 -> Ground Model/1(mg), Add4/2
  Ground Model/2(M1) -> Add3/1
  Bus Selector/4 -> Direction Cosine Matrix to Quaternions/1, Product/1  "<DCM>"
  ModelParam.uavCd/1 -> Propeller Model old Version/10(Cd), Body AeroCenter/3(Cd)
  ModelParam.motorJm/1 -> Propeller Model old Version/7(Jm)
  ModelParam.rotorCm/1 -> Propeller Model old Version/5(Cm)
  MotorRads/1 -> Propeller Model old Version/2(MotorRads)
  Bus Selector/5 -> Propeller Model old Version/8(wb), Ground Model/2(wb), Body AeroCenter/1(wb)  "<wb>"
  ModelParam.uavCCm/1 -> Body AeroCenter/4(CCm)
  Bus Creator/1 -> Force and Moment Model Bus/1
  6DOF Bus/1 -> Bus Selector/1
  Bus Selector/2 -> Ground Model/4(Ve)  "<Ve>"
  Bus Selector/1 -> Ground Model/3(Xe)  "<Xe>"
  Bus Selector/3 -> OnGroundFaceup/1(EulerAng)  "<Eular(rad)>"
  ModelParam.uavMass/1 -> Product1/1
  Bus Selector5/1 -> Product1/2  "<gravity>"
  Environment Model Bus/1 -> Bus Selector5/1
  ModelParam.uavR/1 -> Propeller Model old Version/3(R)
  Bus Selector5/2 -> Propeller Model old Version/9(Vb), Body AeroCenter/2(Vb)  "<Windb>"
  ModelParam.uavDearo/1 -> Propeller Model old Version/4(uavDearo), Body AeroCenter/5(uavDearo)

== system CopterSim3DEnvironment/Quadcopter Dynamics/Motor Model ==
  pwm : Inport
  Constant : Constant  Value=ModelInit_RPM
  Demux : Demux  Outputs=8
  ModelParam.motorCr : Constant  Value=ModelParam_motorCr
  ModelParam.motorT : Constant  Value=ModelParam_motorT
  ModelParam.motorWb : Constant  Value=ModelParam_motorWb
  MotorNonlinearDynamic1 : Subsystem  TreatAsAtomicUnit=on
  MotorNonlinearDynamic2 : Subsystem  TreatAsAtomicUnit=on
  MotorNonlinearDynamic3 : Subsystem  TreatAsAtomicUnit=on
  MotorNonlinearDynamic4 : Subsystem  TreatAsAtomicUnit=on
  MotorNonlinearDynamic5 : Subsystem  TreatAsAtomicUnit=on
  MotorNonlinearDynamic6 : Subsystem  TreatAsAtomicUnit=on
  MotorNonlinearDynamic7 : Subsystem  TreatAsAtomicUnit=on
  MotorNonlinearDynamic8 : Subsystem  TreatAsAtomicUnit=on
  Mux : Mux  Inputs=8
  MotorRads : Outport
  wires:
  Mux/1 -> MotorRads/1
  Demux/1 -> MotorNonlinearDynamic1/5(PWM)
  MotorNonlinearDynamic1/1(radW) -> Mux/1
  ModelParam.motorCr/1 -> MotorNonlinearDynamic1/2(Cr), MotorNonlinearDynamic2/2(Cr), MotorNonlinearDynamic3/2(Cr), MotorNonlinearDynamic4/2(Cr), MotorNonlinearDynamic5/2(Cr), MotorNonlinearDynamic6/2(Cr), MotorNonlinearDynamic8/2(Cr), MotorNonlinearDynamic7/2(Cr)
  ModelParam.motorWb/1 -> MotorNonlinearDynamic1/1(Wb), MotorNonlinearDynamic2/1(Wb), MotorNonlinearDynamic3/1(Wb), MotorNonlinearDynamic4/1(Wb), MotorNonlinearDynamic5/1(Wb), MotorNonlinearDynamic6/1(Wb), MotorNonlinearDynamic8/1(Wb), MotorNonlinearDynamic7/1(Wb)
  Demux/2 -> MotorNonlinearDynamic2/5(PWM)
  Demux/3 -> MotorNonlinearDynamic3/5(PWM)
  Demux/4 -> MotorNonlinearDynamic4/5(PWM)
  Demux/5 -> MotorNonlinearDynamic5/5(PWM)
  Demux/6 -> MotorNonlinearDynamic6/5(PWM)
  Demux/7 -> MotorNonlinearDynamic7/5(PWM)
  Demux/8 -> MotorNonlinearDynamic8/5(PWM)
  ModelParam.motorT/1 -> MotorNonlinearDynamic2/3(motorT), MotorNonlinearDynamic3/3(motorT), MotorNonlinearDynamic4/3(motorT), MotorNonlinearDynamic5/3(motorT), MotorNonlinearDynamic6/3(motorT), MotorNonlinearDynamic8/3(motorT), MotorNonlinearDynamic7/3(motorT), MotorNonlinearDynamic1/3(motorT)
  MotorNonlinearDynamic2/1(radW) -> Mux/2
  MotorNonlinearDynamic8/1(radW) -> Mux/8
  MotorNonlinearDynamic7/1(radW) -> Mux/7
  MotorNonlinearDynamic6/1(radW) -> Mux/6
  MotorNonlinearDynamic5/1(radW) -> Mux/5
  MotorNonlinearDynamic4/1(radW) -> Mux/4
  MotorNonlinearDynamic3/1(radW) -> Mux/3
  pwm/1 -> Demux/1
  Constant/1 -> MotorNonlinearDynamic8/4(ModelInit_RPM), MotorNonlinearDynamic7/4(ModelInit_RPM), MotorNonlinearDynamic6/4(ModelInit_RPM), MotorNonlinearDynamic5/4(ModelInit_RPM), MotorNonlinearDynamic4/4(ModelInit_RPM), MotorNonlinearDynamic3/4(ModelInit_RPM), MotorNonlinearDynamic2/4(ModelInit_RPM), MotorNonlinearDynamic1/4(ModelInit_RPM)

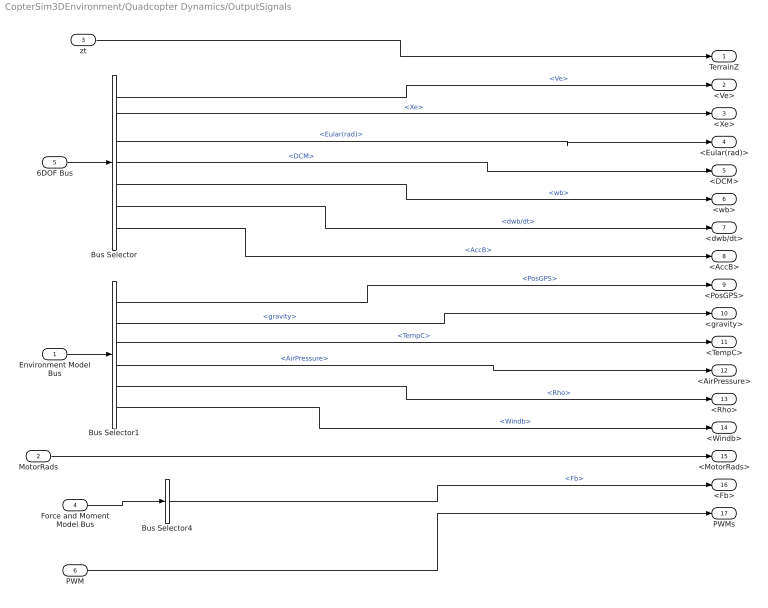
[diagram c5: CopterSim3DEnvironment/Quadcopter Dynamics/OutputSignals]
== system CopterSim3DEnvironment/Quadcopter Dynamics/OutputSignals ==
  Environment Model Bus : Inport
  MotorRads : Inport  Port=2
  zt : Inport  Port=3
  Force and Moment Model Bus : Inport  Port=4
  6DOF Bus : Inport  Port=5
  PWM : Inport  Port=6
  Bus Selector : BusSelector  OutputSignals=Ve,Xe,Eular(rad),DCM,wb,dwb/dt,AccB
  Bus Selector1 : BusSelector  OutputSignals=PosGPS,gravity,TempC,AirPressure,Rho,Windb
  Bus Selector4 : BusSelector  OutputSignals=Fb
  TerrainZ : Outport
  <Ve> : Outport  Port=2
  <Xe> : Outport  Port=3
  <Eular(rad)> : Outport  Port=4
  <DCM> : Outport  Port=5
  <wb> : Outport  Port=6
  <dwb/dt> : Outport  Port=7
  <AccB> : Outport  Port=8
  <PosGPS> : Outport  Port=9
  <gravity> : Outport  Port=10
  <TempC> : Outport  Port=11
  <AirPressure> : Outport  Port=12
  <Rho> : Outport  Port=13
  <Windb> : Outport  Port=14
  <MotorRads> : Outport  Port=15
  <Fb> : Outport  Port=16
  PWMs : Outport  Port=17
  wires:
  Force and Moment Model Bus/1 -> Bus Selector4/1
  MotorRads/1 -> <MotorRads>/1
  Bus Selector1/4 -> <AirPressure>/1  "<AirPressure>"
  Bus Selector/3 -> <Eular(rad)>/1  "<Eular(rad)>"
  Bus Selector1/6 -> <Windb>/1  "<Windb>"
  Bus Selector1/2 -> <gravity>/1  "<gravity>"
  PWM/1 -> PWMs/1
  Bus Selector/4 -> <DCM>/1  "<DCM>"
  Bus Selector/6 -> <dwb/dt>/1  "<dwb/dt>"
  Bus Selector1/1 -> <PosGPS>/1  "<PosGPS>"
  Bus Selector4/1 -> <Fb>/1  "<Fb>"
  Bus Selector/7 -> <AccB>/1  "<AccB>"
  Bus Selector/1 -> <Ve>/1  "<Ve>"
  Bus Selector/5 -> <wb>/1  "<wb>"
  Bus Selector/2 -> <Xe>/1  "<Xe>"
  Bus Selector1/5 -> <Rho>/1  "<Rho>"
  zt/1 -> TerrainZ/1
  Bus Selector1/3 -> <TempC>/1  "<TempC>"
  Environment Model Bus/1 -> Bus Selector1/1
  6DOF Bus/1 -> Bus Selector/1

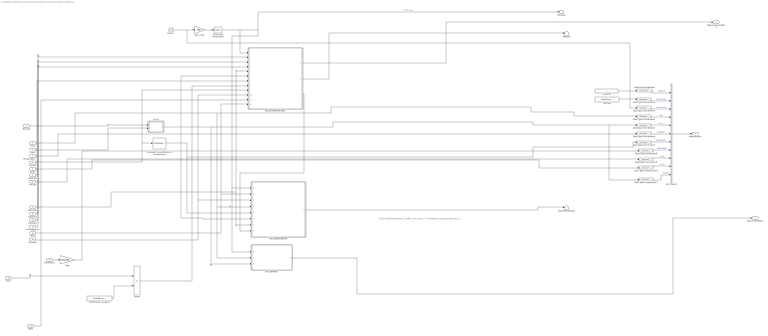
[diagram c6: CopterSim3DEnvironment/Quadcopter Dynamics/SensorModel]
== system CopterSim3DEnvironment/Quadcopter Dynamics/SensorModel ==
  note: Struct MavHILStateQuat{ uint64_t time_usec; /*< Timestamp (microseconds since UNIX epoch or microseconds since system boot)*/ float attitude_quaternion [ 4 ]; /*< Vehicle attitude expressed as normalized quaternion in w, x, y, z order (with 1 0 0 0 being the null-rotation)*/ float rollspeed; /*< Body frame roll / phi angular speed (rad/s)*/ float pitchspeed; /*< Body frame pitch / theta angular speed (rad/s)*/ float yawspeed; /*< Body frame yaw / psi angular speed (rad/s)*/ int32_t lat; /*< Latitude, expressed as * 1E7*/ int32_t lon; /*< Longitude, expressed as * 1E7*/ int32_t alt; /*< Altitude in meters, expressed as * 1000 (millimeters)*/ int16_t vx; /*< Ground X Speed (Latitude), expressed as cm/s*/ int16_t vy; /*< Ground Y Speed (Longitude), expressed as cm/s*/ int16_t vz; /*< Ground Z Speed (Altitude), expressed as cm/s*/ uint16_t ind_airspeed; /*< Indicated airspeed, expressed as cm/s*/ uint16_t true_airspeed; /*< True airspeed, expressed as cm/s*/ int16_t xacc; /*< X acceleration (mg)*/ int16_t yacc; /*< Y acceleration (mg)*/ int16_t zacc; /*< Z acceleration (mg)*/ };
  TerrainZ : Inport
  <Ve> : Inport  Port=2
  <Xe> : Inport  Port=3
  <Eular(rad)> : Inport  Port=4
  <DCM> : Inport  Port=5
  <wb> : Inport  Port=6
  <dwb/dt> : Inport  Port=7
  <AccB> : Inport  Port=8
  <PosGPS> : Inport  Port=9
  <gravity> : Inport  Port=10
  <TempC> : Inport  Port=11
  <AirPressure> : Inport  Port=12
  <Rho> : Inport  Port=13
  <Windb> : Inport  Port=14
  MotorRads : Inport  Port=15
  <Fb> : Inport  Port=16
  PWM : Inport  Port=17
  Bus Creator : BusCreator  Inputs=11  OutDataTypeStr=Bus: MavVehileInfo
  Clock1 : Clock
  CopterID : Constant
  Data Type Conversion : DataTypeConversion  OutDataTypeStr=int32
  Data Type Conversion1 : DataTypeConversion  OutDataTypeStr=uint32
  Data Type Conversion{4..10} (7 alike) : DataTypeConversion  OutDataTypeStr=single
  Data Type Conversion11 : DataTypeConversion  OutDataTypeStr=double
  Data Type Conversion2 : DataTypeConversion  OutDataTypeStr=int32
  Data Type Conversion3 : DataTypeConversion  OutDataTypeStr=double
  Direction Cosine Matrix to Quaternions : sharedtransform/Direction Cosine Matrix  to Quaternions
  Divide : Product  Inputs=*/
  Gain : Gain  Gain=60/2/pi
  Gain_clock : Gain  Gain=1E6
  HILGPSModel : Subsystem
  HILSensorMavModel1 : Subsystem
  HILStateMavModel : Subsystem
  MagDec : Terminator
  MavHILStateQuat : Terminator
  ModelParam.uavMass : Constant  Value=ModelParam_uavMass
  SysTime : Terminator
  UAVType : Constant  Value=ModelParam_uavType
  ZLimit : MATLAB Function  TreatAsAtomicUnit=on
  MavLinkSensorData : Outport
  MavLinkGPSData : Outport  Port=2
  Vehile3DInfo : Outport  Port=3
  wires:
  <Xe>/1 -> ZLimit/2(xe)
  <PosGPS>/1 -> HILStateMavModel/7(PosGPS), HILSensorMavModel1/5(GPSPos)
  <TempC>/1 -> HILSensorMavModel1/3(TempC)
  <AirPressure>/1 -> HILSensorMavModel1/4(pressure)
  Clock1/1 -> Data Type Conversion3/1, Gain_clock/1
  Data Type Conversion1/1 -> HILSensorMavModel1/1(time_usec), SysTime/1, HILGPSModel/1(time_usec), HILStateMavModel/1(time_usec)  "time_usec"
  <gravity>/1 -> HILSensorMavModel1/2(Gravity)
  <Rho>/1 -> HILSensorMavModel1/12(rho), HILStateMavModel/2(pho)
  Gain_clock/1 -> Data Type Conversion1/1
  <DCM>/1 -> HILSensorMavModel1/9(DCMbe), Direction Cosine Matrix to Quaternions/1
  <Eular(rad)>/1 -> Data Type Conversion6/1
  <dwb/dt>/1 -> HILSensorMavModel1/7(dwt)
  <wb>/1 -> HILSensorMavModel1/6(wb), Data Type Conversion10/1, HILStateMavModel/6(wb)
  <Ve>/1 -> HILGPSModel/2(Ve), HILStateMavModel/4(Ve), Data Type Conversion4/1
  TerrainZ/1 -> ZLimit/1(zt)
  CopterID/1 -> Data Type Conversion/1
  HILSensorMavModel1/2(MagDeclination) -> MagDec/1
  <AccB>/1 -> Data Type Conversion9/1
  Divide/1 -> HILSensorMavModel1/8(Ab)
  Data Type Conversion5/1 -> Bus Creator/5  "PosE"
  Data Type Conversion7/1 -> Bus Creator/7  "AngQuatern"
  Data Type Conversion4/1 -> Bus Creator/4  "VelE"
  Data Type Conversion9/1 -> Bus Creator/9  "AccB"
  Data Type Conversion10/1 -> Bus Creator/10  "RateB"
  PWM/1 -> HILSensorMavModel1/11(PWMin)
  Data Type Conversion11/1 -> Bus Creator/11  "PosGPS"
  Data Type Conversion6/1 -> Bus Creator/6  "AngEuler"
  ZLimit/1(Xee) -> Data Type Conversion11/1, Data Type Conversion5/1, HILGPSModel/3(Xe)
  Data Type Conversion/1 -> Bus Creator/1  "copterID"
  Bus Creator/1 -> Vehile3DInfo/1
  <Fb>/1 -> Divide/1
  Gain/1 -> Data Type Conversion8/1
  HILStateMavModel/1(stateOut) -> MavHILStateQuat/1
  Data Type Conversion8/1 -> Bus Creator/8  "MotorRPMS"
  Direction Cosine Matrix to Quaternions/1 -> Data Type Conversion7/1, HILStateMavModel/5(AngQuat)
  UAVType/1 -> Data Type Conversion2/1
  Data Type Conversion3/1 -> Bus Creator/3  "runnedTime"
  HILSensorMavModel1/3(acc) -> HILStateMavModel/8(Accb)
  ModelParam.uavMass/1 -> Divide/2
  Data Type Conversion2/1 -> Bus Creator/2  "vehicleType"
  HILSensorMavModel1/1(SensorOut) -> MavLinkSensorData/1
  HILGPSModel/1(MavLinkGPS) -> MavLinkGPSData/1
  <Windb>/1 -> HILSensorMavModel1/10(windB), HILStateMavModel/3(Vb)
  MotorRads/1 -> Gain/1

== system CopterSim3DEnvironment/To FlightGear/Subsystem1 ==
  copterID : Inport  PortDimensions=1
  vehicleType : Inport  Port=2  PortDimensions=1
  PosE : Inport  Port=3  PortDimensions=3
  AngEuler : Inport  Port=4  PortDimensions=3
  pwms : Inport  Port=5
  Clock : Clock
  Constant{,3..5} (4 alike) : Constant  Value=[0,0,0]
  Constant1 : Constant  Value=[0,0,0,0]
  Subsystem : Subsystem
  toUnReal : Outport
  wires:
  Constant/1 -> Subsystem/4("VelE ")
  PosE/1 -> Subsystem/5(PosE)
  vehicleType/1 -> Subsystem/2(vehicleType)
  Clock/1 -> Subsystem/3(runnedTime)
  Constant4/1 -> Subsystem/10(RateB)
  Constant5/1 -> Subsystem/11(PosGPS)
  AngEuler/1 -> Subsystem/6(AngEuler)
  Subsystem/1(toUnReal) -> toUnReal/1
  Constant3/1 -> Subsystem/9(AccB)
  Constant1/1 -> Subsystem/7(AngQuatern)
  copterID/1 -> Subsystem/1(copterID)
  pwms/1 -> Subsystem/8(MotorRPMS)
